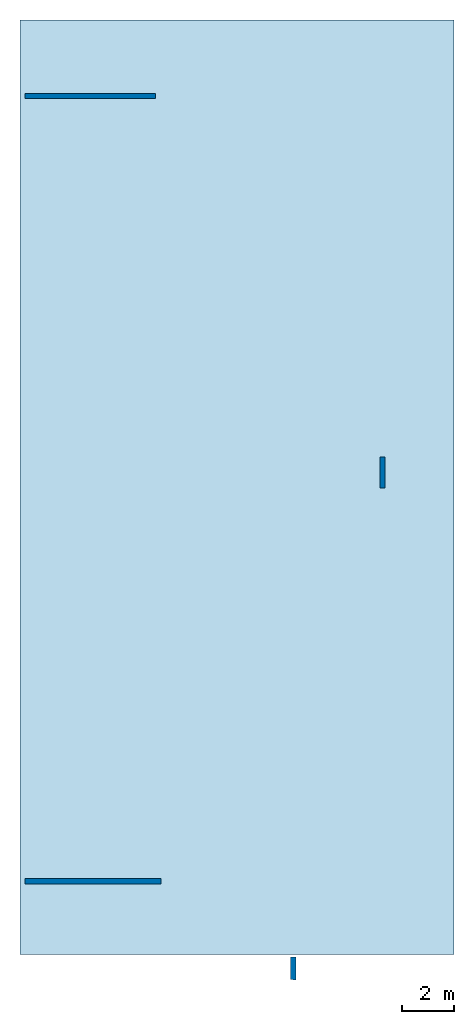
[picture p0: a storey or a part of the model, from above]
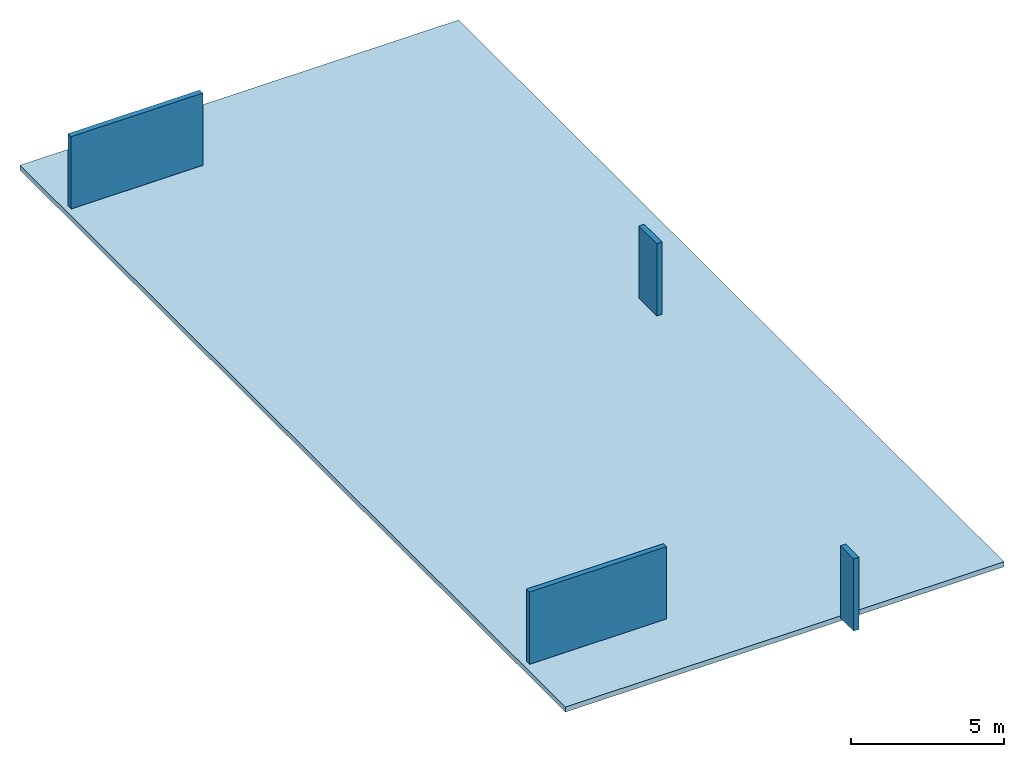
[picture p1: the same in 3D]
Properties of the parts of a building model (IFC2X3)

# File
Description: ViewDefinition [CoordinationView]
File name: Numéro du projet
Time: 2018-01-17T14:54:13
Written by: The EXPRESS Data Manager Version 5.02.0100.07 : 28 Aug 2013
Made in: 20150220_1215(x64) - Exporter 16.0.428.0 - Default UI
Comment: STEP Physical File produced by: The EXPRESS Data Manager Version 5.02.0100.07 : 28 Aug 2013 * Module: EDMstepFileFactory/EDMstandAlone * Creation date: Wed Jan 17 14:54:13 2018 * Host: t2-00 * Database: C:\Users\bim\AppData\Local\Temp\{08BAD956-E43A-4B8B-AAA1-E101C31A570F}\ifc * Database version: 5507 * Database creation date: Wed Jan 17 14:54:12 2018 * Schema: IFC2X3 * Model: DataRepository.ifc * Model creation date: Wed Jan 17 14:54:12 2018 * Header model: DataRepository.ifc_HeaderModel * Header model creation date: Wed Jan 17 14:54:12 2018 * EDMuser: sdai-user * EDMgroup: sdai-group * License ID and type: 5605 : Permanent license. Expiry date: * EDMstepFileFactory options: 020000

# IfcProject, Numéro du projet
LongName: Nom du projet; Phase: Etat du projet

# IfcSite, Default
RefLatitude: 48, 52, 0, 117187; RefLongitude: 2, 19, 59, 880409; RefElevation: 144.95 m
Autre - Adresse du projet: Entrer l'adresse ici; Catégorie: Informations sur le projet; Date de fin du projet: Date de fin; Etat du projet: Etat du projet; Nom du client: Propriétaire; Nom du projet: Nom du projet; Numéro de projet: Numéro du projet

# IfcBuilding
Pset_BuildingCommon - NumberOfStoreys: 2
Autre - Catégorie: Informations sur le projet; Adresse du projet: Entrer l'adresse ici; Date de fin du projet: Date de fin; Etat du projet: Etat du projet; Nom du client: Propriétaire; Nom du projet: Nom du projet; Numéro de projet: Numéro du projet

# IfcBuildingStorey (2)
Autre - Catégorie: Niveaux; Famille: Niveau: Pointe 8 mm; Famille et type: Niveau: Pointe 8 mm; ID du type: Niveau: Pointe 8 mm; Type: Niveau: Pointe 8 mm; Nom de la famille: Niveau
Cotes - Hauteur de calcul: 0 m
Données d'identification - Structure: no; Etage de bâtiment: yes; Nom du type: Pointe 8 mm
Contraintes - Base de l'élévation: Point de base du projet
Graphismes - Couleur: 0; Epaisseur des lignes: 1; Motif des lignes: Centre; Symbole: Marqueur de niveau - Cercle: Marqueur de niveau - Cercle; Valeur par défaut du symbole à l'extrémité 1: no; Valeur par défaut du symbole à l'extrémité 2: yes
Name | LongName = Nom | Elevation (m) = Elévation (m)
AS Dé | AS Dé | -3.39
Dallage | Dallage | -2.89

# IfcColumn: Diamètre de 620 mm 3 (14)
In: AS Dé
Type - ElementType: Diamètre de 620 mm 3; PredefinedType: COLUMN; Material: Béton C25/30
Type - Autre - Catégorie: Poteaux; Nom de la famille: Poteau rond
Type - Cotes - Base du décalage: 0 m; Sommet du décalage: 0 m; Diamètre: 0.62 m
Type - Données d'identification - Nom du type: Diamètre de 620 mm 3
Type - Graphismes - Couleur vue détail faible: 0
Pset_ColumnCommon - IsExternal: no; LoadBearing: no; Slope: 0 deg; Reference: Diamètre de 620 mm 3
Autre - Famille: Poteau rond: Diamètre de 620 mm 3; Famille et type: Poteau rond: Diamètre de 620 mm 3; ID du type: Poteau rond: Diamètre de 620 mm 3; Type: Poteau rond: Diamètre de 620 mm 3
Contraintes - Limite de pièce: yes; Niveau: Niveau: AS Dé; Se déplace avec les quadrillages: yes; Niveau de base: Niveau: AS Dé; Niveau supérieur: Niveau: AS Dé; Décalage inférieur: -0.8 m; Décalage supérieur: -5 m
Cotes - Surface: 4.39225 m2; Volume: 1.26799 m3
Phase de construction - Phase de création: Phase 1
Name (Poteau rond:Diamètre de 620 mm 3:...)
206032
207114
207282
207351
208291
208372
208535
208688
208859
209276
209887
210876
228655
242281

# IfcColumn: Diamètre de 620 mm 3 (21)
In: AS Dé
Type - ElementType: Diamètre de 620 mm 3; PredefinedType: COLUMN
Type - Autre - Catégorie: Poteaux; Nom de la famille: Poteau rond
Type - Cotes - Base du décalage: 0 m; Sommet du décalage: 0 m; Diamètre: 0.62 m
Type - Données d'identification - Nom du type: Diamètre de 620 mm 3
Type - Graphismes - Couleur vue détail faible: 0
Pset_ColumnCommon - IsExternal: no; LoadBearing: no; Reference: Diamètre de 620 mm 3
Autre - Famille: Poteau rond: Diamètre de 620 mm 3; Famille et type: Poteau rond: Diamètre de 620 mm 3; ID du type: Poteau rond: Diamètre de 620 mm 3; Type: Poteau rond: Diamètre de 620 mm 3
Contraintes - Limite de pièce: yes; Niveau: Niveau: AS Dé; Se déplace avec les quadrillages: yes; Niveau supérieur: Niveau: AS Dé; Niveau de base: Niveau: AS Dé; Décalage inférieur: -0.8 m; Décalage supérieur: -5 m
Cotes - Surface: 4.39225 m2; Volume: 1.26799 m3
Phase de construction - Phase de création: Phase 1
Name (Poteau rond:Diamètre de 620 mm 3:...) | Slope (deg)
206899 | 0
207203 | 0
207460 | 0
207694 | 0
208027 | 0
208184 | 0
208926 | 0
209021 | 0
209389 | 0
209458
209581
209734 | 0
210151 | 0
210230
210420 | 0
210743 | 0
211161 | 0
227449 | 0
227636 | 0
228800 | 0
228887 | 0

# IfcColumn: Diamètre de 720 mm 2 (7)
In: AS Dé
Type - ElementType: Diamètre de 720 mm 2; PredefinedType: COLUMN; Material: Béton C25/30
Type - Autre - Catégorie: Poteaux; Nom de la famille: Poteau rond
Type - Cotes - Base du décalage: 0 m; Diamètre: 0.72 m; Sommet du décalage: 0 m
Type - Données d'identification - Nom du type: Diamètre de 720 mm 2
Type - Graphismes - Couleur vue détail faible: 0
Pset_ColumnCommon - IsExternal: no; Reference: Diamètre de 720 mm 2; LoadBearing: no; Slope: 0 deg
Autre - Famille: Poteau rond: Diamètre de 720 mm 2; Famille et type: Poteau rond: Diamètre de 720 mm 2; ID du type: Poteau rond: Diamètre de 720 mm 2; Type: Poteau rond: Diamètre de 720 mm 2
Contraintes - Limite de pièce: yes; Niveau: Niveau: AS Dé; Se déplace avec les quadrillages: yes; Niveau de base: Niveau: AS Dé; Niveau supérieur: Niveau: AS Dé; Décalage inférieur: -0.8 m; Décalage supérieur: -5 m
Cotes - Surface: 5.15722 m2; Volume: 1.71002 m3
Phase de construction - Phase de création: Phase 1
Name (Poteau rond:Diamètre de 720 mm 2:...)
202931
203473
203665
204564
204849
205143
233550

# IfcColumn: Diamètre de 720 mm 2 (5)
In: AS Dé
Type - ElementType: Diamètre de 720 mm 2; PredefinedType: COLUMN
Type - Autre - Catégorie: Poteaux; Nom de la famille: Poteau rond
Type - Cotes - Base du décalage: 0 m; Diamètre: 0.72 m; Sommet du décalage: 0 m
Type - Données d'identification - Nom du type: Diamètre de 720 mm 2
Type - Graphismes - Couleur vue détail faible: 0
Pset_ColumnCommon - IsExternal: no; Reference: Diamètre de 720 mm 2; LoadBearing: no; Slope: 0 deg
Autre - Famille: Poteau rond: Diamètre de 720 mm 2; Famille et type: Poteau rond: Diamètre de 720 mm 2; ID du type: Poteau rond: Diamètre de 720 mm 2; Type: Poteau rond: Diamètre de 720 mm 2
Contraintes - Limite de pièce: yes; Niveau: Niveau: AS Dé; Se déplace avec les quadrillages: yes; Décalage inférieur: -0.8 m; Décalage supérieur: -5 m; Niveau de base: Niveau: AS Dé; Niveau supérieur: Niveau: AS Dé
Cotes - Surface: 5.15722 m2; Volume: 1.71002 m3
Phase de construction - Phase de création: Phase 1
Name (Poteau rond:Diamètre de 720 mm 2:...)
202781
203304
203964
204067
229069

# IfcColumn: Diamètre de820 mm 4, Poteau rond:Diamètre de820 mm 4:224566
In: AS Dé
Type - ElementType: Diamètre de820 mm 4; PredefinedType: COLUMN; Material: Béton C25/30
Type - Autre - Catégorie: Poteaux; Nom de la famille: Poteau rond
Type - Cotes - Base du décalage: 0 m; Sommet du décalage: 0 m; Diamètre: 0.82 m
Type - Données d'identification - Nom du type: Diamètre de820 mm 4
Type - Graphismes - Couleur vue détail faible: 0
Pset_ColumnCommon - IsExternal: no; LoadBearing: no; Slope: 0 deg; Reference: Diamètre de820 mm 4
Autre - Famille: Poteau rond: Diamètre de820 mm 4; Famille et type: Poteau rond: Diamètre de820 mm 4; ID du type: Poteau rond: Diamètre de820 mm 4; Type: Poteau rond: Diamètre de820 mm 4
Contraintes - Limite de pièce: yes; Niveau: Niveau: AS Dé; Se déplace avec les quadrillages: yes; Niveau de base: Niveau: AS Dé; Niveau supérieur: Niveau: AS Dé; Décalage inférieur: -0.8 m; Décalage supérieur: -5 m
Cotes - Surface: 5.9379 m2; Volume: 2.21801 m3
Phase de construction - Phase de création: Phase 1

# IfcColumn: Diamètre de820 mm 4 (4)
In: AS Dé
Type - ElementType: Diamètre de820 mm 4; PredefinedType: COLUMN
Type - Autre - Catégorie: Poteaux; Nom de la famille: Poteau rond
Type - Cotes - Base du décalage: 0 m; Sommet du décalage: 0 m; Diamètre: 0.82 m
Type - Données d'identification - Nom du type: Diamètre de820 mm 4
Type - Graphismes - Couleur vue détail faible: 0
Pset_ColumnCommon - IsExternal: no; LoadBearing: no; Slope: 0 deg; Reference: Diamètre de820 mm 4
Autre - Famille: Poteau rond: Diamètre de820 mm 4; Famille et type: Poteau rond: Diamètre de820 mm 4; ID du type: Poteau rond: Diamètre de820 mm 4; Type: Poteau rond: Diamètre de820 mm 4
Contraintes - Limite de pièce: yes; Niveau: Niveau: AS Dé; Se déplace avec les quadrillages: yes; Niveau de base: Niveau: AS Dé; Niveau supérieur: Niveau: AS Dé; Décalage inférieur: -0.8 m; Décalage supérieur: -5 m
Cotes - Surface: 5.9379 m2; Volume: 2.21801 m3
Phase de construction - Phase de création: Phase 1
Name (Poteau rond:Diamètre de820 mm 4:...)
224173
224334
227778
229426

# IfcSlab: Base rectangulaire:1000mm x 1000mm x 800mm ht (6)
In: AS Dé
PredefinedType: FLOOR; Material: Béton - Béton coulé sur place
Pset_SlabCommon - LoadBearing: yes; IsExternal: no; Reference: 1000mm x 1000mm x 800mm ht
Autre - Catégorie: Fondations; Famille: Base rectangulaire: 1000mm x 1000mm x 800mm ht; Famille et type: Base rectangulaire: 1000mm x 1000mm x 800mm ht; ID du type: Base rectangulaire: 1000mm x 1000mm x 800mm ht; Type: Base rectangulaire: 1000mm x 1000mm x 800mm ht; Nom de la famille: Base rectangulaire
Contraintes - Décalage: 0 m; Se déplace avec les quadrillages: yes; Niveau: Niveau: AS Dé; Hôte: Niveau : AS Dé
Cotes - Elévation à la base: -4.19 m; Elévation en haut: -3.39 m; Largeur: 1 m; Longueur: 1 m; Surface: 1 m2; Volume: 0.8 m3; Epaisseur: 0.8 m
Matériaux et finitions - Matériau structurel: Béton C25/30
Phase de construction - Phase de création: Phase 1
Résultats de l'analyse - Volume: 0.8 m3
Structure - Activer le modèle analytique: yes; Enrobage d'armature - Autres faces: Paramètres de l'enrobage d'armature: Enrobage d'armature 1; Enrobage d'armature - Face inférieure: Paramètres de l'enrobage d'armature: Enrobage d'armature 1; Enrobage d'armature - Face supérieure: Paramètres de l'enrobage d'armature: Enrobage d'armature 1
Données d'identification - Nom du type: 1000mm x 1000mm x 800mm ht
Name (Base rectangulaire:1000mm x 1000mm x 800mm ht:...)
154719
155861
156030
190198
226099
229297

# IfcSlab: Base rectangulaire:2800mm x 3250mm x 800mm ht 2, Base rectangulaire:2800mm x 3250mm x 800mm ht 2:233097
In: AS Dé
PredefinedType: FLOOR; Material: Béton - Béton coulé sur place
Pset_SlabCommon - LoadBearing: yes; IsExternal: no; Reference: 2800mm x 3250mm x 800mm ht 2
Autre - Catégorie: Fondations; Famille: Base rectangulaire: 2800mm x 3250mm x 800mm ht 2; Famille et type: Base rectangulaire: 2800mm x 3250mm x 800mm ht 2; ID du type: Base rectangulaire: 2800mm x 3250mm x 800mm ht 2; Type: Base rectangulaire: 2800mm x 3250mm x 800mm ht 2; Nom de la famille: Base rectangulaire
Contraintes - Décalage: 0 m; Niveau: Niveau: AS Dé; Se déplace avec les quadrillages: yes; Hôte: Niveau : AS Dé
Cotes - Elévation à la base: -4.19 m; Elévation en haut: -3.39 m; Largeur: 3.25 m; Longueur: 2.8 m; Surface: 9.1 m2; Volume: 7.28 m3; Epaisseur: 0.8 m
Matériaux et finitions - Matériau structurel: Béton C25/30
Phase de construction - Phase de création: Phase 1
Résultats de l'analyse - Volume: 7.28 m3
Structure - Activer le modèle analytique: yes; Enrobage d'armature - Autres faces: Paramètres de l'enrobage d'armature: Enrobage d'armature 1; Enrobage d'armature - Face inférieure: Paramètres de l'enrobage d'armature: Enrobage d'armature 1; Enrobage d'armature - Face supérieure: Paramètres de l'enrobage d'armature: Enrobage d'armature 1
Données d'identification - Nom du type: 2800mm x 3250mm x 800mm ht 2

# IfcSlab: Base rectangulaire:800mm x 800mm x 800mm ht (27)
In: AS Dé
PredefinedType: FLOOR; Material: Béton - Béton coulé sur place
Pset_SlabCommon - LoadBearing: yes; Reference: 800mm x 800mm x 800mm ht; IsExternal: no
Autre - Catégorie: Fondations; Famille: Base rectangulaire: 800mm x 800mm x 800mm ht; Famille et type: Base rectangulaire: 800mm x 800mm x 800mm ht; ID du type: Base rectangulaire: 800mm x 800mm x 800mm ht; Type: Base rectangulaire: 800mm x 800mm x 800mm ht; Nom de la famille: Base rectangulaire
Contraintes - Hôte: Niveau : AS Dé; Niveau: Niveau: AS Dé; Se déplace avec les quadrillages: yes
Cotes - Largeur: 0.8 m; Longueur: 0.8 m; Surface: 0.64 m2; Volume: 0.512 m3; Epaisseur: 0.8 m
Phase de construction - Phase de création: Phase 1
Résultats de l'analyse - Volume: 0.512 m3
Structure - Activer le modèle analytique: yes; Enrobage d'armature - Autres faces: Paramètres de l'enrobage d'armature: Enrobage d'armature 1; Enrobage d'armature - Face inférieure: Paramètres de l'enrobage d'armature: Enrobage d'armature 1; Enrobage d'armature - Face supérieure: Paramètres de l'enrobage d'armature: Enrobage d'armature 1
Données d'identification - Nom du type: 800mm x 800mm x 800mm ht
Name (Base rectangulaire:800mm x 800mm x 800mm ht:...) | Décalage (m) | Elévation à la base (m) | Elévation en haut (m) | Matériau structurel
146805 | 0 | -4.19 | -3.39 | Béton C25/30
147110 | 0 | -4.19 | -3.39 | Béton C25/30
147503 | 0 | -4.19 | -3.39 | Béton C25/30
147828 | 0 | -4.19 | -3.39 | Béton C25/30
148199 | 0 | -4.19 | -3.39 | Béton C25/30
148516 | 0 | -4.19 | -3.39 | Béton C25/30
149043 | 0 | -4.19 | -3.39 | Béton C25/30
149596 | -0.0005 | -4.1905 | -3.3905 | Béton C25/30
149937 | 0 | -4.19 | -3.39 | Béton C25/30
150036 | 0 | -4.19 | -3.39 | Béton C25/30
150345 | 0 | -4.19 | -3.39 | Béton C25/30
151525 | 0 | -4.19 | -3.39 | Béton C25/30
152021 | 0 | -4.19 | -3.39 | Béton C25/30
152306 | 0 | -4.19 | -3.39 | Béton C25/30
152694 | 0 | -4.19 | -3.39 | Béton C25/30
166548 | 0 | -4.19 | -3.39 | Béton C25/30
166703 | 0 | -4.19 | -3.39 | Béton C25/30
183909 | 0 | -4.19 | -3.39 | Béton C25/30
184972 | 0 | -4.19 | -3.39 | Béton C25/30
185326 | 0 | -4.19 | -3.39 | Béton C25/30
186069 | 0 | -4.19 | -3.39 | Béton C25/30
188888 | 0 | -4.19 | -3.39 | Béton C25/30
225780 | 0 | -4.19 | -3.39 | Béton C25/30
228253 | 0 | -4.19 | -3.39 | Béton C25/30
228394 | 0 | -4.19 | -3.39 | Béton C25/30
228449 | 0 | -4.19 | -3.39 | Béton C25/30
242173 | 0 | -4.19 | -3.39 | Béton - Béton coulé sur place

# IfcSlab: Base rectangulaire:900mm x 3550mm x 800mm ht (4)
In: AS Dé
PredefinedType: FLOOR; Material: Béton - Béton coulé sur place
Pset_SlabCommon - LoadBearing: yes; IsExternal: no; Reference: 900mm x 3550mm x 800mm ht
Autre - Catégorie: Fondations; Famille: Base rectangulaire: 900mm x 3550mm x 800mm ht; Famille et type: Base rectangulaire: 900mm x 3550mm x 800mm ht; ID du type: Base rectangulaire: 900mm x 3550mm x 800mm ht; Type: Base rectangulaire: 900mm x 3550mm x 800mm ht; Nom de la famille: Base rectangulaire
Contraintes - Décalage: 0 m; Niveau: Niveau: AS Dé; Se déplace avec les quadrillages: yes; Hôte: Niveau : AS Dé
Cotes - Elévation à la base: -4.19 m; Elévation en haut: -3.39 m; Largeur: 3.55 m; Longueur: 0.9 m; Surface: 3.195 m2; Volume: 2.556 m3; Epaisseur: 0.8 m
Matériaux et finitions - Matériau structurel: Béton C25/30
Phase de construction - Phase de création: Phase 1
Résultats de l'analyse - Volume: 2.556 m3
Structure - Activer le modèle analytique: yes; Enrobage d'armature - Autres faces: Paramètres de l'enrobage d'armature: Enrobage d'armature 1; Enrobage d'armature - Face inférieure: Paramètres de l'enrobage d'armature: Enrobage d'armature 1; Enrobage d'armature - Face supérieure: Paramètres de l'enrobage d'armature: Enrobage d'armature 1
Données d'identification - Nom du type: 900mm x 3550mm x 800mm ht
Name (Base rectangulaire:900mm x 3550mm x 800mm ht:...)
173560
173901
174195
174483

# IfcSlab: Base rectangulaire:900mm x 900mm x 800mm ht (7)
In: AS Dé
PredefinedType: FLOOR; Material: Béton - Béton coulé sur place
Pset_SlabCommon - LoadBearing: yes; IsExternal: no; Reference: 900mm x 900mm x 800mm ht
Autre - Catégorie: Fondations; Famille: Base rectangulaire: 900mm x 900mm x 800mm ht; Famille et type: Base rectangulaire: 900mm x 900mm x 800mm ht; ID du type: Base rectangulaire: 900mm x 900mm x 800mm ht; Type: Base rectangulaire: 900mm x 900mm x 800mm ht; Nom de la famille: Base rectangulaire
Contraintes - Se déplace avec les quadrillages: yes; Niveau: Niveau: AS Dé; Hôte: Niveau : AS Dé
Cotes - Largeur: 0.9 m; Longueur: 0.9 m; Surface: 0.81 m2; Volume: 0.648 m3; Epaisseur: 0.8 m
Matériaux et finitions - Matériau structurel: Béton C25/30
Phase de construction - Phase de création: Phase 1
Résultats de l'analyse - Volume: 0.648 m3
Structure - Activer le modèle analytique: yes; Enrobage d'armature - Autres faces: Paramètres de l'enrobage d'armature: Enrobage d'armature 1; Enrobage d'armature - Face inférieure: Paramètres de l'enrobage d'armature: Enrobage d'armature 1; Enrobage d'armature - Face supérieure: Paramètres de l'enrobage d'armature: Enrobage d'armature 1
Données d'identification - Nom du type: 900mm x 900mm x 800mm ht
Name (Base rectangulaire:900mm x 900mm x 800mm ht:...) | Décalage (m) | Elévation à la base (m) | Elévation en haut (m)
153124 | 0 | -4.19 | -3.39
153645 | 0 | -4.19 | -3.39
153784 | 0 | -4.19 | -3.39
154114 | 0 | -4.19 | -3.39
154181 | -0.0005 | -4.1905 | -3.3905
185122 | 0 | -4.19 | -3.39
229227 | 0 | -4.19 | -3.39

# IfcSlab: Sol:Dallage 20 cm, Sol:Dallage 20 cm:234033
In: Dallage
PredefinedType: FLOOR; Material: Béton C25/30 0.2 m
Pset_SlabCommon - LoadBearing: yes; IsExternal: no; Reference: Dallage 20 cm; ThermalTransmittance: 5.23 kg/K/s3; PitchAngle: 0 deg
Autre - Catégorie: Sols; Famille: Sol: Dallage 20 cm; Famille et type: Sol: Dallage 20 cm; ID du type: Sol: Dallage 20 cm; Type: Sol: Dallage 20 cm; Nom de la famille: Sol
Contraintes - Lié au volume: no; Limite de pièce: yes; Décalage par rapport au niveau: 0 m; Niveau: Niveau: Dallage
Cotes - Elévation à la base: -3.09 m; Elévation au niveau du noyau inférieur: -3.09 m; Elévation au niveau du noyau supérieur: -2.89 m; Elévation en haut: -2.89 m; Epaisseur: 0.2 m; Périmètre: 104.58 m; Surface: 592.072 m2; Volume: 118.414 m3
Phase de construction - Phase de création: Phase 1
Structure - Activer le modèle analytique: yes; Enrobage d'armature - Autres faces: Paramètres de l'enrobage d'armature: Enrobage d'armature 1; Structure: yes; Enrobage d'armature - Face inférieure: Paramètres de l'enrobage d'armature: Enrobage d'armature 1; Enrobage d'armature - Face supérieure: Paramètres de l'enrobage d'armature: Enrobage d'armature 1
Construction - Epaisseur par défaut: 0.2 m; Fonction: Intérieur
Données d'identification - Nom du type: Dallage 20 cm
Graphismes - Couleur vue détail faible: 0
Matériaux et finitions - Matériau structurel: Béton C25/30
Propriétés analytiques - Rugosité: 3; Coefficient d'absorbance: 0.7; Coefficient de transfert de chaleur (U): 5.23; Masse thermique: 302220; Résistance thermique (R): 0.191205

# IfcWallStandardCase: Mur de base:Générique - 200 mm (47)
Type - PredefinedType: STANDARD; Material: Béton C25/30 0.2 m
Type - Autre - Catégorie: Murs; Nom de la famille: Mur de base
Type - Construction - Fonction: Extérieur; Largeur: 0.2 m; Retournement aux extrémités: Aucun(e); Retournement aux insertions: Ne pas retourner
Type - Données d'identification - Nom du type: Générique - 200 mm
Type - Graphismes - Couleur vue détail faible: 0
Type - Matériaux et finitions - Matériau structurel: Béton C25/30
Type - Propriétés analytiques - Coefficient d'absorbance: 0.7; Coefficient de transfert de chaleur (U): 5.23; Masse thermique: 302220; Résistance thermique (R): 0.191205; Rugosité: 3
Autre - Famille: Mur de base: Générique - 200 mm; Famille et type: Mur de base: Générique - 200 mm; ID du type: Mur de base: Générique - 200 mm; Type: Mur de base: Générique - 200 mm
Contraintes - Décalage inférieur: 0 m; Extension inférieure: 0 m; Extension supérieure: 0 m; Lié au volume: no; Ligne de justification: Axe du mur; Limite de pièce: yes; Partie inférieure attachée: no; Partie supérieure attachée: no
Phase de construction - Phase de création: Phase 1
Pset_WallCommon - Reference: Générique - 200 mm; ExtendToStructure: no; IsExternal: yes; ThermalTransmittance: 5.23 kg/K/s3
Name (Mur de base:Générique - 200 mm:...) | In | Contrainte inférieure | Contrainte supérieure | Décalage supérieur (m) | Hauteur non contrainte (m) | Longueur (m) | Surface (m2) | Volume (m3) | Activer le modèle analytique = Structure = LoadBearing | Enrobage d'armature - Autres faces = Enrobage d'armature - Face extérieure = Enrobage d'armature - Face intérieure | Utilisation structurelle
137256 | Dallage | Niveau: Dallage | Niveau: Niveau 1 | 0 | 2.89 | 5.18 | 14.3922 | 2.87844 | yes | Paramètres de l'enrobage d'armature: Enrobage d'armature 1 | Porteur
176051 | AS Dé | Niveau: AS Dé | Niveau: Niveau 1 | 0 | 3.39 | 1.7815 | 5.70029 | 1.14006 | yes | Paramètres de l'enrobage d'armature: Enrobage d'armature 1 | Porteur
177401 | AS Dé | Niveau: AS Dé | Niveau: Niveau 1 | 0 | 3.39 | 1.7815 | 6.03928 | 1.20786 | yes | Paramètres de l'enrobage d'armature: Enrobage d'armature 1 | Porteur
186828 | AS Dé | Niveau: AS Dé | Niveau: Niveau 1 | 0 | 3.39 | 1.2705 | 4.30699 | 0.861399 | yes | Paramètres de l'enrobage d'armature: Enrobage d'armature 1 | Porteur
187755 | Dallage | Niveau: Dallage | Niveau: Niveau 1 | 0 | 2.89 | 1.2705 | 3.38274 | 0.676549 | yes | Paramètres de l'enrobage d'armature: Enrobage d'armature 1 | Porteur
196356 | AS Dé | Niveau: AS Dé | Niveau: Niveau 1 | 0 | 3.39 | 35.8 | 114.898 | 22.9796 | yes | Paramètres de l'enrobage d'armature: Enrobage d'armature 1 | Porteur
239041 | AS Dé | Niveau: AS Dé | Niveau: Dallage | 0 | 0.5 | 4.2145 | 1.29435 | 0.25887 | yes | Paramètres de l'enrobage d'armature: Enrobage d'armature 1 | Porteur
239412 | AS Dé | Niveau: AS Dé | Niveau: Dallage | 0 | 0.5 | 5.18 | 2.49 | 0.498 | yes | Paramètres de l'enrobage d'armature: Enrobage d'armature 1 | Porteur
239424 | AS Dé | Niveau: AS Dé | Niveau: Niveau 1 | 0 | 3.39 | 5.18 | 16.8822 | 3.37644 | yes | Paramètres de l'enrobage d'armature: Enrobage d'armature 1 | Porteur
239440 | AS Dé | Niveau: AS Dé | Niveau: Dallage | 0 | 0.5 | 1.7815 | 0.84075 | 0.16815 | yes | Paramètres de l'enrobage d'armature: Enrobage d'armature 1 | Porteur
239444 | AS Dé | Niveau: AS Dé | Niveau: Niveau 1 | 0 | 3.39 | 4.2145 | 13.7633 | 2.75265 | yes | Paramètres de l'enrobage d'armature: Enrobage d'armature 1 | Porteur
239446 | AS Dé | Niveau: AS Dé | Niveau: Dallage | 0 | 0.5 | 1.7815 | 0.79075 | 0.15815 | yes | Paramètres de l'enrobage d'armature: Enrobage d'armature 1 | Porteur
239458 | AS Dé | Niveau: AS Dé | Niveau: Dallage | 0 | 0.5 | 1.2705 | 0.53525 | 0.10705 | yes | Paramètres de l'enrobage d'armature: Enrobage d'armature 1 | Porteur
239462 | AS Dé | Niveau: AS Dé | Niveau: Dallage | 0 | 0.5 | 1.2705 | 0.58525 | 0.11705 | yes | Paramètres de l'enrobage d'armature: Enrobage d'armature 1 | Porteur
239464 | AS Dé | Niveau: AS Dé | Niveau: Niveau 1 | 0 | 3.39 | 2.944 | 9.30216 | 1.86043 | yes | Paramètres de l'enrobage d'armature: Enrobage d'armature 1 | Porteur
243820 | AS Dé | Niveau: AS Dé | Niveau: Niveau 1 | 0 | 3.39 | 1.3997 | 4.43407 | 0.880946 | yes | Paramètres de l'enrobage d'armature: Enrobage d'armature 1 | Porteur
243925 | AS Dé | Niveau: AS Dé | Niveau: Niveau 1 | 0 | 3.39 | 1.6 | 5.763 | 1.1526 | yes | Paramètres de l'enrobage d'armature: Enrobage d'armature 1 | Porteur
244144 | AS Dé | Niveau: AS Dé | Niveau: Niveau 1 | 0 | 3.39 | 0.459593 | 1.55802 | 0.311604 | yes | Paramètres de l'enrobage d'armature: Enrobage d'armature 1 | Porteur
244227 | AS Dé | Niveau: AS Dé | Niveau: Niveau 1 | 0.05 | 3.44 | 2.4741 | 9.19889 | 1.83978 | yes | Paramètres de l'enrobage d'armature: Enrobage d'armature 1 | Porteur
244342 | Dallage | Niveau: Dallage | Niveau: Niveau 1 | 0 | 2.89 | 0.869148 | 2.53793 | 0.502584 | yes | Paramètres de l'enrobage d'armature: Enrobage d'armature 1 | Porteur
245189 | AS Dé | Niveau: AS Dé | Niveau: Niveau 1 | 0 | 3.39 | 6.15292 | 20.8584 | 4.17168 | yes | Paramètres de l'enrobage d'armature: Enrobage d'armature 1 | Porteur
247623 | AS Dé | Niveau: AS Dé | Niveau: Niveau 1 | 0 | 3.39 | 18.066 | 61.9217 | 12.3843 | no |  | Non porteur
247715 | AS Dé | Niveau: AS Dé | Niveau: Niveau 1 | 0 | 3.39 | 3.735 | 11.9837 | 2.39673 | no |  | Non porteur
247869 | AS Dé | Niveau: AS Dé | Niveau: Niveau 1 | 0 | 3.39 | 11.99 | 40.9851 | 8.19702 | no |  | Non porteur
248265 | AS Dé | Niveau: AS Dé | Niveau: Niveau 1 | 0 | 3.39 | 5.16 | 17.4924 | 3.49848 | yes | Paramètres de l'enrobage d'armature: Enrobage d'armature 1 | Porteur
248647 | AS Dé | Niveau: AS Dé | Niveau: Niveau 1 | 0 | 3.39 | 14.79 | 49.7991 | 9.95982 | yes | Paramètres de l'enrobage d'armature: Enrobage d'armature 1 | Porteur
249231 | AS Dé | Niveau: AS Dé | Niveau: Niveau 1 | 0 | 3.39 | 4.75 | 15.4245 | 3.0849 | yes | Paramètres de l'enrobage d'armature: Enrobage d'armature 1 | Porteur
249621 | AS Dé | Niveau: AS Dé | Niveau: Niveau 1 | 0 | 3.39 | 5.18 | 17.5602 | 3.51204 | yes | Paramètres de l'enrobage d'armature: Enrobage d'armature 1 | Porteur
249783 | AS Dé | Niveau: AS Dé | Niveau: Niveau 1 | 0 | 3.39 | 5.18 | 16.8822 | 3.37644 | yes | Paramètres de l'enrobage d'armature: Enrobage d'armature 1 | Porteur
250594 | AS Dé | Niveau: AS Dé | Niveau: Niveau 1 | 0 | 3.39 | 0.469593 | 0.91392 | 0.182784 | yes | Paramètres de l'enrobage d'armature: Enrobage d'armature 1 | Porteur
250682 | AS Dé | Niveau: AS Dé | Niveau: Niveau 1 | 0 | 3.39 | 1.0959 | 3.71511 | 0.743022 | yes | Paramètres de l'enrobage d'armature: Enrobage d'armature 1 | Porteur
250983 | AS Dé | Niveau: AS Dé | Niveau: Niveau 1 | 0 | 3.39 | 5.16 | 16.8144 | 3.36288 | yes | Paramètres de l'enrobage d'armature: Enrobage d'armature 1 | Porteur
251114 | AS Dé | Niveau: AS Dé | Niveau: Niveau 1 | 0 | 3.39 | 5.18 | 16.8822 | 3.37644 | yes | Paramètres de l'enrobage d'armature: Enrobage d'armature 1 | Porteur
251586 | AS Dé | Niveau: AS Dé | Niveau: Niveau 1 | 0 | 3.39 | 5.17 | 17.5263 | 3.50526 | yes | Paramètres de l'enrobage d'armature: Enrobage d'armature 1 | Porteur
251759 | AS Dé | Niveau: AS Dé | Niveau: Niveau 1 | 0 | 3.39 | 5.18 | 16.8822 | 3.37644 | yes | Paramètres de l'enrobage d'armature: Enrobage d'armature 1 | Porteur
252478 | Dallage | Niveau: Dallage | Niveau: Niveau 1 | 0 | 2.89 | 5.18 | 14.9702 | 2.99404 | yes | Paramètres de l'enrobage d'armature: Enrobage d'armature 1 | Porteur
252833 | AS Dé | Niveau: AS Dé | Niveau: Niveau 1 | 0 | 3.39 | 33.01 | 105.342 | 21.0684 | yes | Paramètres de l'enrobage d'armature: Enrobage d'armature 1 | Porteur
253998 | AS Dé | Niveau: AS Dé | Niveau: Niveau 1 | 0 | 3.39 | 5.18 | 16.8822 | 3.37644 | yes | Paramètres de l'enrobage d'armature: Enrobage d'armature 1 | Porteur
254574 | AS Dé | Niveau: AS Dé | Niveau: Niveau 1 | 0 | 3.39 | 2.79 | 9.4581 | 1.89162 | yes | Paramètres de l'enrobage d'armature: Enrobage d'armature 1 | Porteur
254969 | AS Dé | Niveau: AS Dé | Niveau: Niveau 1 | 0 | 3.39 | 3.3 | 10.509 | 2.1018 | yes | Paramètres de l'enrobage d'armature: Enrobage d'armature 1 | Porteur
255380 | AS Dé | Niveau: AS Dé | Niveau: Niveau 1 | 0 | 3.39 | 2.44 | 7.5936 | 1.51533 | yes | Paramètres de l'enrobage d'armature: Enrobage d'armature 1 | Porteur
255880 | AS Dé | Niveau: AS Dé | Niveau: Niveau 1 | 0 | 3.39 | 5.16 | 16.8144 | 3.36288 | yes | Paramètres de l'enrobage d'armature: Enrobage d'armature 1 | Porteur
256364 | AS Dé | Niveau: AS Dé | Niveau: Niveau 1 | 0 | 3.39 | 5.17 | 17.1873 | 3.43746 | yes | Paramètres de l'enrobage d'armature: Enrobage d'armature 1 | Porteur
256865 | AS Dé | Niveau: AS Dé | Niveau: Niveau 1 | 0 | 3.39 | 9 | 30.51 | 6.102 | yes | Paramètres de l'enrobage d'armature: Enrobage d'armature 1 | Porteur
257163 | AS Dé | Niveau: AS Dé | Niveau: Niveau 1 | 0 | 3.39 | 5.18 | 16.8822 | 3.37644 | yes | Paramètres de l'enrobage d'armature: Enrobage d'armature 1 | Porteur
257414 | AS Dé | Niveau: AS Dé | Niveau: Niveau 1 | 0 | 3.39 | 1.514 | 4.45446 | 0.890892 | yes | Paramètres de l'enrobage d'armature: Enrobage d'armature 1 | Porteur
258784 | AS Dé | Niveau: AS Dé | Niveau: Niveau 1 | 0 | 3.39 | 4.5 | 14.577 | 2.9154 | no |  | Non porteur
